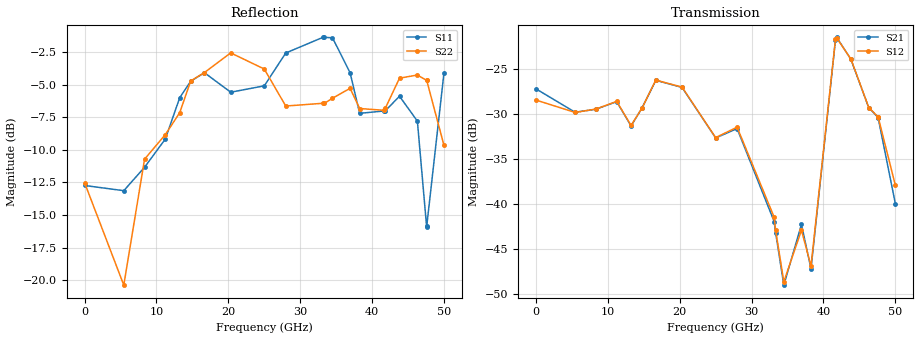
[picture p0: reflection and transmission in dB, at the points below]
!Keysight Technologies,N5245B,MY58422270,A.16.20.02
!Date: Thursday, March 05, 2026 01:38:16
!Correction: S11(C  2-Port  )
!S21(C  2-Port  )
!S12(C  2-Port  )
!S22(C  2-Port  )
!S2P File: Measurements: S11, S21, S12, S22:
# Hz S  dB  R 50
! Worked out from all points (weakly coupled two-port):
!   3201 points, 10 MHz to 50 GHz, reference 50 ohm
!   highest |S21| = -21.44 dB at 41.85 GHz (marker M1); lowest = -49.0 dB at 34.49 GHz (marker M2)
!   lowest |S11| = -15.9 dB at 47.58 GHz (marker M3), VSWR 1.38, Z = 45.2 + j14.7 ohm
!   |S11| at or under -10 dB: start of sweep to 9.797 GHz; 11.44 GHz to 11.86 GHz (421.3 MHz wide, 3.62 % of centre); 46.75 GHz to 48.31 GHz (1.563 GHz wide, 3.29 % of centre)
!   |S22| runs from -20.4 to -2.5 dB; largest |S21 - S12| = 0.0089
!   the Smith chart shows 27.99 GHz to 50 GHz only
!   S11 on the Smith chart (normalised r, x): 27.99 GHz: 0.20, +0.57; 33.14 GHz: 0.67, +2.69; 36.94 GHz: 1.52, -1.91; 43.81 GHz: 0.68, -0.92; 47.59 GHz: 0.92, +0.30; 50 GHz: 0.54, -1.08
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1e7  -12.73 -4.1  -27.17 2.6  -28.42 5.6  -12.52 32.7
5.462034e9  -13.13 -135.0  -29.78 153.5  -29.80 153.5  -20.38 -138.2
8.352081e9  -11.33 170.2  -29.44 31.9  -29.42 32.0  -10.71 -157.5
1.124213e10  -9.16 100.0  -28.60 -71.1  -28.57 -71.3  -8.82 89.4
1.324173e10  -5.99 60.4  -31.30 -119.2  -31.25 -119.4  -7.14 -20.0
1.477267e10  -4.73 13.0  -29.29 -146.9  -29.30 -147.1  -4.70 -89.4
1.667854e10  -4.07 -44.4  -26.22 158.1  -26.20 158.2  -4.06 -141.8
2.033406e10  -5.57 -126.9  -27.01 40.2  -26.98 39.6  -2.55 153.6
2.5005e10  -5.08 171.3  -32.64 -67.4  -32.60 -68.1  -3.79 70.6
2.798878e10  -2.56 119.0  -31.60 -132.0  -31.44 -133.8  -6.63 16.5
3.3144e10  -1.36 38.9  -41.95 12.9  -41.47 10.8  -6.42 -126.2
3.334708e10  -1.36 35.4  -43.20 3.6  -42.93 -1.3  -6.43 -130.7
3.448748e10  -1.39 15.7  -49.03 -117.2  -48.65 -112.9  -6.03 -155.8
3.694011e10  -4.08 -37.6  -42.27 96.5  -42.91 97.4  -5.27 156.6
3.826797e10  -7.19 -20.5  -47.21 101.8  -46.90 -89.0  -6.82 133.8
4.167354e10  -7.01 -56.5  -21.70 -60.3  -21.65 -61.2  -6.96 113.3
4.184538e10  -6.99 -56.6  -21.44 -76.7  -21.51 -77.8  -6.79 112.2
4.381374e10  -5.88 -80.4  -23.88 170.9  -23.85 171.3  -4.49 92.1
4.629762e10  -7.79 -146.0  -29.26 35.0  -29.25 33.2  -4.25 57.8
4.757861e10  -15.88 99.4  -30.35 -13.5  -30.28 -14.2  -4.66 42.2
4.759423e10  -15.87 96.7  -30.37 -13.6  -30.27 -14.1  -4.66 42.0
5e10  -4.07 -77.9  -39.95 -121.2  -37.91 -124.9  -9.66 6.6
